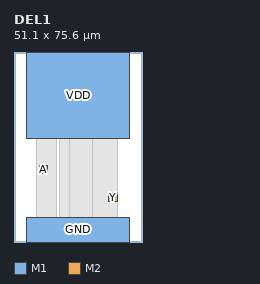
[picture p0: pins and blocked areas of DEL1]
MACRO DEL1
  CLASS CORE ;
  ORIGIN 0 0 ;
  SIZE 51.100 BY 75.600 ;
  SYMMETRY X Y ;
  SITE TR1um_access_site ;
  PIN VDD
    DIRECTION INOUT ;
    USE POWER ;
    PORT
      LAYER M1 ;
        RECT 5.000 41.000 46.100 75.600 ;
    END
  END VDD
  PIN GND
    DIRECTION INOUT ;
    USE GROUND ;
    PORT
      LAYER M1 ;
        RECT 5.000 0.000 46.100 9.800 ;
    END
  END GND
  PIN A
    DIRECTION INPUT ;
    USE SIGNAL ;
    PORT
      LAYER M2 ;
        RECT 10.100 27.100 13.500 30.500 ;
    END
  END A
  PIN Y
    DIRECTION OUTPUT ;
    USE SIGNAL ;
    PORT
      LAYER M2 ;
        RECT 37.600 16.100 41.000 19.500 ;
    END
  END Y
  OBS
    LAYER M1 ;
      RECT 10.100 22.000 13.700 30.500 ;
    LAYER M1 ;
      RECT 9.100 6.400 16.900 51.200 ;
    LAYER M1 ;
      RECT 18.100 6.400 27.200 51.200 ;
    LAYER M1 ;
      RECT 22.100 6.400 31.600 51.200 ;
    LAYER M1 ;
      RECT 31.100 6.400 41.000 51.200 ;
    LAYER V1 ;
      RECT 38.600 17.100 40.000 18.500 ;
    LAYER V1 ;
      RECT 11.100 28.100 12.500 29.500 ;
  END
END DEL1
